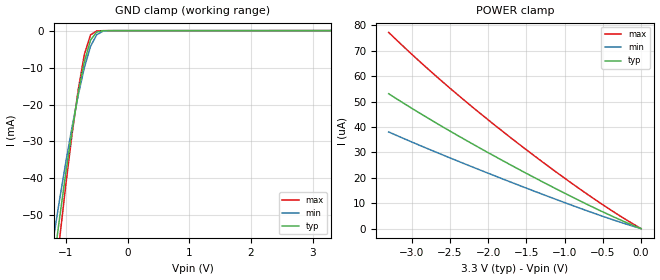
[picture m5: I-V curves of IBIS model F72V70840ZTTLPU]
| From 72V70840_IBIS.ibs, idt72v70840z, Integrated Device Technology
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|   Model F72V70840ZTTLPU
[Model]   F72V70840ZTTLPU
Model_type   Input
Vinl =  0.000V
Vinh =  3.000V
Vmeas =  1.500V
C_comp   3.00pF   NA   NA
[Temperature Range]   25.00   85.00   -40.00
[Voltage Range]   3.30V   3.00V   3.60V
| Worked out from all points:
|   GND clamp passes 1 mA (typ) near -0.53 V on its own axis
[GND_clamp]
| voltage   I(typ)   I(min)   I(max)
-3.3V     -384mA     -331mA     -438mA
-1.2V     -63.26mA   -56.1mA    -71.52mA
-1.1V     -50.49mA   -45.54mA   -56.18mA
-1V       -38.38mA   -35.52mA   -41.6mA
-900mV    -27.12mA   -26.12mA   -28.07mA
-800mV    -16.94mA   -17.5mA    -16.04mA
-700mV    -8.368mA   -9.983mA   -6.426mA
-600mV    -2.564mA   -4.248mA   -1.149mA
-500mV    -373uA     -1.12mA    -86.38uA
-400mV    -42.06uA   -183uA     -21.59uA
-300mV    -14.24uA   -29.21uA   -19.35uA
3.3V      33.47nA    2.845uA    -4.754uA
[POWER_clamp]
| voltage   I(typ)   I(min)   I(max)
-3.3V     53.07uA    38.05uA    77.19uA
-3V       47.4uA     34.14uA    68.65uA
-2.6V     40.18uA    29.11uA    57.89uA
-2.2V     33.28uA    24.23uA    47.72uA
-1.7V     25uA       18.29uA    35.68uA
-1.2V     17.06uA    12.53uA    24.27uA
-700mV    9.495uA    6.987uA    13.5uA
-300mV    3.86uA     2.845uA    5.494uA
0V        33.47nA    45.35nA    36.35nA
